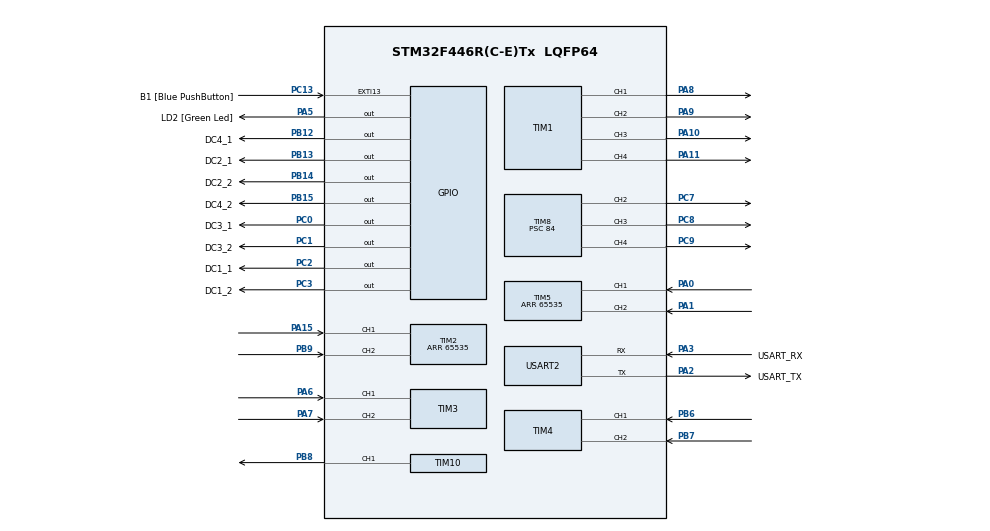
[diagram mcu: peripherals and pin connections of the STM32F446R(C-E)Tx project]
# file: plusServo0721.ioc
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Mcu.Family=STM32F4
Mcu.Name=STM32F446R(C-E)Tx
Mcu.Package=LQFP64
NVIC.PriorityGroup=NVIC_PRIORITYGROUP_0
NVIC.TIM1_BRK_TIM9_IRQn=true\:0\:0\:false\:false\:true\:true\:true\:true
NVIC.TIM1_UP_TIM10_IRQn=true\:0\:0\:false\:false\:true\:true\:true\:true
NVIC.TIM2_IRQn=true\:0\:0\:false\:false\:true\:true\:true\:true
NVIC.TIM3_IRQn=true\:0\:0\:false\:false\:true\:true\:true\:true
NVIC.TIM4_IRQn=true\:0\:0\:false\:false\:true\:true\:true\:true
NVIC.TIM5_IRQn=true\:0\:0\:false\:false\:true\:true\:true\:true
PA0-WKUP.Signal=S_TIM5_CH1
PA1.Signal=S_TIM5_CH2
PA10.Signal=S_TIM1_CH3
PA11.Signal=S_TIM1_CH4
PA13.GPIO_Label=TMS
PA13.Mode=Serial_Wire
PA13.Signal=SYS_JTMS-SWDIO
PA14.GPIO_Label=TCK
PA14.Mode=Serial_Wire
PA14.Signal=SYS_JTCK-SWCLK
PA15.Signal=S_TIM2_CH1_ETR
PA2.GPIO_Label=USART_TX
PA2.Mode=Asynchronous
PA2.Signal=USART2_TX
PA3.GPIO_Label=USART_RX
PA3.Mode=Asynchronous
PA3.Signal=USART2_RX
PA5.GPIO_Label=LD2 [Green Led]
PA5.Signal=GPIO_Output
PA6.Signal=S_TIM3_CH1
PA7.Signal=S_TIM3_CH2
PA8.Signal=S_TIM1_CH1
PA9.Signal=S_TIM1_CH2
PB12.GPIO_Label=DC4_1
PB12.Signal=GPIO_Output
PB13.GPIO_Label=DC2_1
PB13.Signal=GPIO_Output
PB14.GPIO_Label=DC2_2
PB14.Signal=GPIO_Output
PB15.GPIO_Label=DC4_2
PB15.Signal=GPIO_Output
PB3.GPIO_Label=SWO
PB3.Signal=SYS_JTDO-SWO
PB6.Signal=S_TIM4_CH1
PB7.Signal=S_TIM4_CH2
PB8.Signal=S_TIM10_CH1
PB9.Signal=S_TIM2_CH2
PC0.GPIO_Label=DC3_1
PC0.Signal=GPIO_Output
PC1.GPIO_Label=DC3_2
PC1.Signal=GPIO_Output
PC13.GPIO_Label=B1 [Blue PushButton]
PC13.GPIO_ModeDefaultEXTI=GPIO_MODE_IT_FALLING
PC13.Signal=GPXTI13
PC14-OSC32_IN.Mode=LSE-External-Oscillator
PC14-OSC32_IN.Signal=RCC_OSC32_IN
PC15-OSC32_OUT.Mode=LSE-External-Oscillator
PC15-OSC32_OUT.Signal=RCC_OSC32_OUT
PC2.GPIO_Label=DC1_1
PC2.Signal=GPIO_Output
PC3.GPIO_Label=DC1_2
PC3.Signal=GPIO_Output
PC7.Signal=S_TIM8_CH2
PC8.Signal=S_TIM8_CH3
PC9.Signal=S_TIM8_CH4
PH0-OSC_IN.Mode=HSE-External-Oscillator
PH0-OSC_IN.Signal=RCC_OSC_IN
PH1-OSC_OUT.Mode=HSE-External-Oscillator
PH1-OSC_OUT.Signal=RCC_OSC_OUT
ProjectManager.HeapSize=0x200
ProjectManager.StackSize=0x400
ProjectManager.TargetToolchain=STM32CubeIDE
RCC.48MHZClocksFreq_Value=84000000
RCC.AHBFreq_Value=84000000
RCC.APB1CLKDivider=RCC_HCLK_DIV2
RCC.APB1Freq_Value=42000000
RCC.APB1TimFreq_Value=84000000
RCC.APB2Freq_Value=84000000
RCC.APB2TimFreq_Value=84000000
RCC.CortexFreq_Value=84000000
RCC.FLatency-AdvancedSettings=FLASH_LATENCY_2
RCC.HCLKFreq_Value=84000000
RCC.HSE_VALUE=8000000
RCC.HSI_VALUE=16000000
RCC.PLLN=336
RCC.PLLP=RCC_PLLP_DIV4
RCC.SYSCLKFreq_VALUE=84000000
RCC.SYSCLKSource=RCC_SYSCLKSOURCE_PLLCLK
RCC.USBFreq_Value=168000000
RCC.VCOOutputFreq_Value=336000000
SH.S_TIM10_CH1.0=TIM10_CH1,PWM Generation1 CH1
SH.S_TIM1_CH1.0=TIM1_CH1,PWM Generation1 CH1
SH.S_TIM1_CH2.0=TIM1_CH2,PWM Generation2 CH2
SH.S_TIM1_CH3.0=TIM1_CH3,PWM Generation3 CH3
SH.S_TIM1_CH4.0=TIM1_CH4,PWM Generation4 CH4
SH.S_TIM2_CH1_ETR.0=TIM2_CH1,Encoder_Interface
SH.S_TIM2_CH2.0=TIM2_CH2,Encoder_Interface
SH.S_TIM3_CH1.0=TIM3_CH1,Encoder_Interface
SH.S_TIM3_CH2.0=TIM3_CH2,Encoder_Interface
SH.S_TIM4_CH1.0=TIM4_CH1,Encoder_Interface
SH.S_TIM4_CH2.0=TIM4_CH2,Encoder_Interface
SH.S_TIM5_CH1.0=TIM5_CH1,Encoder_Interface
SH.S_TIM5_CH2.0=TIM5_CH2,Encoder_Interface
SH.S_TIM8_CH2.0=TIM8_CH2,PWM Generation2 CH2
SH.S_TIM8_CH3.0=TIM8_CH3,PWM Generation3 CH3
SH.S_TIM8_CH4.0=TIM8_CH4,PWM Generation4 CH4
TIM1.Channel-PWM\ Generation1\ CH1=TIM_CHANNEL_1
TIM1.Channel-PWM\ Generation2\ CH2=TIM_CHANNEL_2
TIM1.Channel-PWM\ Generation3\ CH3=TIM_CHANNEL_3
TIM1.Channel-PWM\ Generation4\ CH4=TIM_CHANNEL_4
TIM10.Channel=TIM_CHANNEL_1
TIM10.OCMode_PWM=TIM_OCMODE_PWM1
TIM2.EncoderMode=TIM_ENCODERMODE_TI12
TIM2.Period=65535
TIM3.EncoderMode=TIM_ENCODERMODE_TI12
TIM3.IC1Polarity=TIM_ICPOLARITY_FALLING
TIM3.IC2Polarity=TIM_ICPOLARITY_FALLING
TIM4.EncoderMode=TIM_ENCODERMODE_TI12
TIM5.EncoderMode=TIM_ENCODERMODE_TI12
TIM5.IC1Polarity=TIM_ICPOLARITY_FALLING
TIM5.IC2Polarity=TIM_ICPOLARITY_FALLING
TIM5.Period=65535
TIM8.Channel-PWM\ Generation2\ CH2=TIM_CHANNEL_2
TIM8.Channel-PWM\ Generation3\ CH3=TIM_CHANNEL_3
TIM8.Channel-PWM\ Generation4\ CH4=TIM_CHANNEL_4
TIM8.Prescaler=84
USART2.VirtualMode=VM_ASYNC
VP_TIM10_VS_ClockSourceINT.Mode=Enable_Timer
VP_TIM1_VS_ClockSourceINT.Mode=Internal
VP_TIM1_VS_OPM.Mode=OPM_bit
board=NUCLEO-F446RE

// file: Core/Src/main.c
/* USER CODE BEGIN Header */
/**
  ******************************************************************************
  * @file           : main.c
  * @brief          : Main program body
  ******************************************************************************
  * @attention
  *
  * Copyright (c) 2022 STMicroelectronics.
  * All rights reserved.
  *
  * This software is licensed under terms that can be found in the LICENSE file
  * in the root directory of this software component.
  * If no LICENSE file comes with this software, it is provided AS-IS.
  *
  ******************************************************************************
  */
/* USER CODE END Header */
#include "main.h"

 TIM_HandleTypeDef htim1;
TIM_HandleTypeDef htim2;
TIM_HandleTypeDef htim3;
TIM_HandleTypeDef htim4;
TIM_HandleTypeDef htim5;
TIM_HandleTypeDef htim8;
TIM_HandleTypeDef htim10;

UART_HandleTypeDef huart2;

void SystemClock_Config(void);
static void MX_GPIO_Init(void);
static void MX_USART2_UART_Init(void);
static void MX_TIM2_Init(void);
static void MX_TIM3_Init(void);
static void MX_TIM4_Init(void);
static void MX_TIM5_Init(void);
static void MX_TIM1_Init(void);
static void MX_TIM10_Init(void);
static void MX_TIM8_Init(void);

/* USER CODE BEGIN 0 */

uint32_t counter2 = 0;
uint32_t counter3 = 0;
uint32_t counter4 = 0;
uint32_t counter5 = 0;

int16_t count2 = 0;
int16_t count3 = 0;
int16_t count4 = 0;
int16_t count5 = 0;

void HAL_TIM_IC_CaptureCallback(TIM_HandleTypeDef *htim)
{
	if(htim == &htim2){
		counter2 = __HAL_TIM_GET_COUNTER(htim);
		count2 = (int16_t)counter2;
	}
	else if(htim == &htim3){
			counter3 = __HAL_TIM_GET_COUNTER(htim);
			count3 = (int16_t)counter3;
		}
	else if(htim == &htim4){
			counter4 = __HAL_TIM_GET_COUNTER(htim);
			count4 = (int16_t)counter4;
		}
	else if(htim == &htim5){
			counter5 = __HAL_TIM_GET_COUNTER(htim);
			count5 = (int16_t)counter5;
		}

}

/* USER CODE END 0 */

int main(void)
{

  /* MCU Configuration--------------------------------------------------------*/

  /* Reset of all peripherals, Initializes the Flash interface and the Systick. */
  HAL_Init();

  /* Configure the system clock */
  SystemClock_Config();

  /* Initialize all configured peripherals */
  MX_GPIO_Init();
  MX_USART2_UART_Init();
  MX_TIM2_Init();
  MX_TIM3_Init();
  MX_TIM4_Init();
  MX_TIM5_Init();
  MX_TIM1_Init();
  MX_TIM10_Init();
  MX_TIM8_Init();
  /* USER CODE BEGIN 2 */
  // Encoder
  HAL_TIM_Encoder_Start_IT(&htim2, TIM_CHANNEL_ALL);
  HAL_TIM_Encoder_Start_IT(&htim3, TIM_CHANNEL_ALL);
  HAL_TIM_Encoder_Start_IT(&htim4, TIM_CHANNEL_ALL);
  HAL_TIM_Encoder_Start_IT(&htim5, TIM_CHANNEL_ALL);

  // start DC motor PWM
  HAL_TIM_PWM_Start(&htim1, TIM_CHANNEL_1);
  HAL_TIM_PWM_Start(&htim1, TIM_CHANNEL_2);
  HAL_TIM_PWM_Start(&htim1, TIM_CHANNEL_3);
  HAL_TIM_PWM_Start(&htim1, TIM_CHANNEL_4);

  // Servo PWM
  HAL_TIM_PWM_Start(&htim8, TIM_CHANNEL_2);
  HAL_TIM_PWM_Start(&htim8, TIM_CHANNEL_3);
  HAL_TIM_PWM_Start(&htim8, TIM_CHANNEL_4);
  HAL_TIM_PWM_Start(&htim10, TIM_CHANNEL_1);
  htim8.Instance->CCR2 = 75;
  htim8.Instance->CCR3 = 75;
  htim8.Instance->CCR4 = 75;
  htim10.Instance->CCR1 = 75;
  HAL_Delay(1000);
  /*
   Encoder: TIM2~TIM5
   DC motor: TIM1
   Servo: TIM8, TIM10
   */
  /* USER CODE END 2 */

  /* Infinite loop */
  /* USER CODE BEGIN WHILE */
  while (1)
  {
	  // DC motor PWM
	  /*htim1.Instance-> CCR1 = 80;
	  htim1.Instance-> CCR2 = 80;
	  htim1.Instance-> CCR3 = 80;
	  htim1.Instance-> CCR4 = 80;*/

 	  int i=0;
 	  while(i<10)
 	  {
 		  htim8.Instance->CCR2 = 32-i;
 		  htim8.Instance->CCR3 = 37+i;
 		  htim8.Instance->CCR4 = 44-i;
 		  htim10.Instance->CCR1 = 54+i;
 		  i++;
 		  HAL_Delay(1000);
 	  }
	  // four wheels go forward
	  /*for(int i=0;i<4;i++){
	  	  		  int a=1;
	  	  		  int b=0;
	  	  		  HAL_GPIO_WritePin(GPIOC, DC1_1_Pin, a);
	  	  		  HAL_GPIO_WritePin(GPIOC, DC1_2_Pin, b);
	  	  		  HAL_GPIO_WritePin(GPIOB, DC2_1_Pin, a);
	  	  		  HAL_GPIO_WritePin(GPIOB, DC2_2_Pin, b);
	  	  		  HAL_GPIO_WritePin(GPIOC, DC3_1_Pin, a);
	  	  		  HAL_GPIO_WritePin(GPIOC, DC3_2_Pin, b);
	  	  		  HAL_GPIO_WritePin(GPIOB, DC4_1_Pin, a);
	  	  		  HAL_GPIO_WritePin(GPIOB, DC4_2_Pin, b);
	  	  		  HAL_Delay(1000);
	  }
	  // four wheels go backward
	  for(int i=0;i<4;i++){
				  int a=0;
				  int b=1;
				  HAL_GPIO_WritePin(GPIOC, DC1_1_Pin, a);
				  HAL_GPIO_WritePin(GPIOC, DC1_2_Pin, b);
	  	  		  HAL_GPIO_WritePin(GPIOB, DC2_1_Pin, a);
	  	  		  HAL_GPIO_WritePin(GPIOB, DC2_2_Pin, b);
	  	  		  HAL_GPIO_WritePin(GPIOC, DC3_1_Pin, a);
	  	  		  HAL_GPIO_WritePin(GPIOC, DC3_2_Pin, b);
	  	  		  HAL_GPIO_WritePin(GPIOB, DC4_1_Pin, a);
	  	  		  HAL_GPIO_WritePin(GPIOB, DC4_2_Pin, b);
				  HAL_Delay(1000);
	  }*/

    /* USER CODE END WHILE */

    /* USER CODE BEGIN 3 */
  }
  htim1.Instance-> CCR1 = 0;
  htim1.Instance-> CCR2 = 0;
  htim1.Instance-> CCR3 = 0;
  htim1.Instance-> CCR4 = 0;
  for(int i=0;i<4;i++){
	  int a=0;
	  int b=0;
	  HAL_GPIO_WritePin(GPIOC, DC1_1_Pin, a);
	  HAL_GPIO_WritePin(GPIOC, DC1_2_Pin, b);
	  HAL_GPIO_WritePin(GPIOC, DC3_1_Pin, a);
	  HAL_GPIO_WritePin(GPIOC, DC3_2_Pin, b);
	  HAL_Delay(1000);
  }
  /* USER CODE END 3 */
}

void SystemClock_Config(void)
{
  RCC_OscInitTypeDef RCC_OscInitStruct = {0};
  RCC_ClkInitTypeDef RCC_ClkInitStruct = {0};

  /** Configure the main internal regulator output voltage
  */
  __HAL_RCC_PWR_CLK_ENABLE();
  __HAL_PWR_VOLTAGESCALING_CONFIG(PWR_REGULATOR_VOLTAGE_SCALE3);

  /** Initializes the RCC Oscillators according to the specified parameters
  * in the RCC_OscInitTypeDef structure.
  */
  RCC_OscInitStruct.OscillatorType = RCC_OSCILLATORTYPE_HSI;
  RCC_OscInitStruct.HSIState = RCC_HSI_ON;
  RCC_OscInitStruct.HSICalibrationValue = RCC_HSICALIBRATION_DEFAULT;
  RCC_OscInitStruct.PLL.PLLState = RCC_PLL_ON;
  RCC_OscInitStruct.PLL.PLLSource = RCC_PLLSOURCE_HSI;
  RCC_OscInitStruct.PLL.PLLM = 8;
  RCC_OscInitStruct.PLL.PLLN = 90;
  RCC_OscInitStruct.PLL.PLLP = RCC_PLLP_DIV2;
  RCC_OscInitStruct.PLL.PLLQ = 2;
  RCC_OscInitStruct.PLL.PLLR = 2;
  if (HAL_RCC_OscConfig(&RCC_OscInitStruct) != HAL_OK)
  {
    Error_Handler();
  }

  /** Initializes the CPU, AHB and APB buses clocks
  */
  RCC_ClkInitStruct.ClockType = RCC_CLOCKTYPE_HCLK|RCC_CLOCKTYPE_SYSCLK
                              |RCC_CLOCKTYPE_PCLK1|RCC_CLOCKTYPE_PCLK2;
  RCC_ClkInitStruct.SYSCLKSource = RCC_SYSCLKSOURCE_PLLCLK;
  RCC_ClkInitStruct.AHBCLKDivider = RCC_SYSCLK_DIV1;
  RCC_ClkInitStruct.APB1CLKDivider = RCC_HCLK_DIV4;
  RCC_ClkInitStruct.APB2CLKDivider = RCC_HCLK_DIV1;

  if (HAL_RCC_ClockConfig(&RCC_ClkInitStruct, FLASH_LATENCY_2) != HAL_OK)
  {
    Error_Handler();
  }
}

static void MX_TIM1_Init(void)
{

  TIM_ClockConfigTypeDef sClockSourceConfig = {0};
  TIM_MasterConfigTypeDef sMasterConfig = {0};
  TIM_OC_InitTypeDef sConfigOC = {0};
  TIM_BreakDeadTimeConfigTypeDef sBreakDeadTimeConfig = {0};

  htim1.Instance = TIM1;
  htim1.Init.Prescaler = 0;
  htim1.Init.CounterMode = TIM_COUNTERMODE_UP;
  htim1.Init.Period = 65535;
  htim1.Init.ClockDivision = TIM_CLOCKDIVISION_DIV1;
  htim1.Init.RepetitionCounter = 0;
  htim1.Init.AutoReloadPreload = TIM_AUTORELOAD_PRELOAD_DISABLE;
  if (HAL_TIM_Base_Init(&htim1) != HAL_OK)
  {
    Error_Handler();
  }
  sClockSourceConfig.ClockSource = TIM_CLOCKSOURCE_INTERNAL;
  if (HAL_TIM_ConfigClockSource(&htim1, &sClockSourceConfig) != HAL_OK)
  {
    Error_Handler();
  }
  if (HAL_TIM_PWM_Init(&htim1) != HAL_OK)
  {
    Error_Handler();
  }
  if (HAL_TIM_OnePulse_Init(&htim1, TIM_OPMODE_SINGLE) != HAL_OK)
  {
    Error_Handler();
  }
  sMasterConfig.MasterOutputTrigger = TIM_TRGO_RESET;
  sMasterConfig.MasterSlaveMode = TIM_MASTERSLAVEMODE_DISABLE;
  if (HAL_TIMEx_MasterConfigSynchronization(&htim1, &sMasterConfig) != HAL_OK)
  {
    Error_Handler();
  }
  sConfigOC.OCMode = TIM_OCMODE_PWM1;
  sConfigOC.Pulse = 0;
  sConfigOC.OCPolarity = TIM_OCPOLARITY_HIGH;
  sConfigOC.OCNPolarity = TIM_OCNPOLARITY_HIGH;
  sConfigOC.OCFastMode = TIM_OCFAST_DISABLE;
  sConfigOC.OCIdleState = TIM_OCIDLESTATE_RESET;
  sConfigOC.OCNIdleState = TIM_OCNIDLESTATE_RESET;
  if (HAL_TIM_PWM_ConfigChannel(&htim1, &sConfigOC, TIM_CHANNEL_1) != HAL_OK)
  {
    Error_Handler();
  }
  if (HAL_TIM_PWM_ConfigChannel(&htim1, &sConfigOC, TIM_CHANNEL_2) != HAL_OK)
  {
    Error_Handler();
  }
  if (HAL_TIM_PWM_ConfigChannel(&htim1, &sConfigOC, TIM_CHANNEL_3) != HAL_OK)
  {
    Error_Handler();
  }
  if (HAL_TIM_PWM_ConfigChannel(&htim1, &sConfigOC, TIM_CHANNEL_4) != HAL_OK)
  {
    Error_Handler();
  }
  sBreakDeadTimeConfig.OffStateRunMode = TIM_OSSR_DISABLE;
  sBreakDeadTimeConfig.OffStateIDLEMode = TIM_OSSI_DISABLE;
  sBreakDeadTimeConfig.LockLevel = TIM_LOCKLEVEL_OFF;
  sBreakDeadTimeConfig.DeadTime = 0;
  sBreakDeadTimeConfig.BreakState = TIM_BREAK_DISABLE;
  sBreakDeadTimeConfig.BreakPolarity = TIM_BREAKPOLARITY_HIGH;
  sBreakDeadTimeConfig.AutomaticOutput = TIM_AUTOMATICOUTPUT_DISABLE;
  if (HAL_TIMEx_ConfigBreakDeadTime(&htim1, &sBreakDeadTimeConfig) != HAL_OK)
  {
    Error_Handler();
  }
  HAL_TIM_MspPostInit(&htim1);

}

static void MX_TIM2_Init(void)
{

  TIM_Encoder_InitTypeDef sConfig = {0};
  TIM_MasterConfigTypeDef sMasterConfig = {0};

  htim2.Instance = TIM2;
  htim2.Init.Prescaler = 0;
  htim2.Init.CounterMode = TIM_COUNTERMODE_UP;
  htim2.Init.Period = 65535;
  htim2.Init.ClockDivision = TIM_CLOCKDIVISION_DIV1;
  htim2.Init.AutoReloadPreload = TIM_AUTORELOAD_PRELOAD_DISABLE;
  sConfig.EncoderMode = TIM_ENCODERMODE_TI12;
  sConfig.IC1Polarity = TIM_ICPOLARITY_RISING;
  sConfig.IC1Selection = TIM_ICSELECTION_DIRECTTI;
  sConfig.IC1Prescaler = TIM_ICPSC_DIV1;
  sConfig.IC1Filter = 0;
  sConfig.IC2Polarity = TIM_ICPOLARITY_RISING;
  sConfig.IC2Selection = TIM_ICSELECTION_DIRECTTI;
  sConfig.IC2Prescaler = TIM_ICPSC_DIV1;
  sConfig.IC2Filter = 0;
  if (HAL_TIM_Encoder_Init(&htim2, &sConfig) != HAL_OK)
  {
    Error_Handler();
  }
  sMasterConfig.MasterOutputTrigger = TIM_TRGO_RESET;
  sMasterConfig.MasterSlaveMode = TIM_MASTERSLAVEMODE_DISABLE;
  if (HAL_TIMEx_MasterConfigSynchronization(&htim2, &sMasterConfig) != HAL_OK)
  {
    Error_Handler();
  }

}

static void MX_TIM3_Init(void)
{

  TIM_Encoder_InitTypeDef sConfig = {0};
  TIM_MasterConfigTypeDef sMasterConfig = {0};

  htim3.Instance = TIM3;
  htim3.Init.Prescaler = 0;
  htim3.Init.CounterMode = TIM_COUNTERMODE_UP;
  htim3.Init.Period = 65535;
  htim3.Init.ClockDivision = TIM_CLOCKDIVISION_DIV1;
  htim3.Init.AutoReloadPreload = TIM_AUTORELOAD_PRELOAD_DISABLE;
  sConfig.EncoderMode = TIM_ENCODERMODE_TI12;
  sConfig.IC1Polarity = TIM_ICPOLARITY_FALLING;
  sConfig.IC1Selection = TIM_ICSELECTION_DIRECTTI;
  sConfig.IC1Prescaler = TIM_ICPSC_DIV1;
  sConfig.IC1Filter = 0;
  sConfig.IC2Polarity = TIM_ICPOLARITY_FALLING;
  sConfig.IC2Selection = TIM_ICSELECTION_DIRECTTI;
  sConfig.IC2Prescaler = TIM_ICPSC_DIV1;
  sConfig.IC2Filter = 0;
  if (HAL_TIM_Encoder_Init(&htim3, &sConfig) != HAL_OK)
  {
    Error_Handler();
  }
  sMasterConfig.MasterOutputTrigger = TIM_TRGO_RESET;
  sMasterConfig.MasterSlaveMode = TIM_MASTERSLAVEMODE_DISABLE;
  if (HAL_TIMEx_MasterConfigSynchronization(&htim3, &sMasterConfig) != HAL_OK)
  {
    Error_Handler();
  }

}

static void MX_TIM4_Init(void)
{

  TIM_Encoder_InitTypeDef sConfig = {0};
  TIM_MasterConfigTypeDef sMasterConfig = {0};

  htim4.Instance = TIM4;
  htim4.Init.Prescaler = 0;
  htim4.Init.CounterMode = TIM_COUNTERMODE_UP;
  htim4.Init.Period = 65535;
  htim4.Init.ClockDivision = TIM_CLOCKDIVISION_DIV1;
  htim4.Init.AutoReloadPreload = TIM_AUTORELOAD_PRELOAD_DISABLE;
  sConfig.EncoderMode = TIM_ENCODERMODE_TI12;
  sConfig.IC1Polarity = TIM_ICPOLARITY_RISING;
  sConfig.IC1Selection = TIM_ICSELECTION_DIRECTTI;
  sConfig.IC1Prescaler = TIM_ICPSC_DIV1;
  sConfig.IC1Filter = 0;
  sConfig.IC2Polarity = TIM_ICPOLARITY_RISING;
  sConfig.IC2Selection = TIM_ICSELECTION_DIRECTTI;
  sConfig.IC2Prescaler = TIM_ICPSC_DIV1;
  sConfig.IC2Filter = 0;
  if (HAL_TIM_Encoder_Init(&htim4, &sConfig) != HAL_OK)
  {
    Error_Handler();
  }
  sMasterConfig.MasterOutputTrigger = TIM_TRGO_RESET;
  sMasterConfig.MasterSlaveMode = TIM_MASTERSLAVEMODE_DISABLE;
  if (HAL_TIMEx_MasterConfigSynchronization(&htim4, &sMasterConfig) != HAL_OK)
  {
    Error_Handler();
  }

}

static void MX_TIM5_Init(void)
{

  TIM_Encoder_InitTypeDef sConfig = {0};
  TIM_MasterConfigTypeDef sMasterConfig = {0};

  htim5.Instance = TIM5;
  htim5.Init.Prescaler = 0;
  htim5.Init.CounterMode = TIM_COUNTERMODE_UP;
  htim5.Init.Period = 65535;
  htim5.Init.ClockDivision = TIM_CLOCKDIVISION_DIV1;
  htim5.Init.AutoReloadPreload = TIM_AUTORELOAD_PRELOAD_DISABLE;
  sConfig.EncoderMode = TIM_ENCODERMODE_TI12;
  sConfig.IC1Polarity = TIM_ICPOLARITY_FALLING;
  sConfig.IC1Selection = TIM_ICSELECTION_DIRECTTI;
  sConfig.IC1Prescaler = TIM_ICPSC_DIV1;
  sConfig.IC1Filter = 0;
  sConfig.IC2Polarity = TIM_ICPOLARITY_FALLING;
  sConfig.IC2Selection = TIM_ICSELECTION_DIRECTTI;
  sConfig.IC2Prescaler = TIM_ICPSC_DIV1;
  sConfig.IC2Filter = 0;
  if (HAL_TIM_Encoder_Init(&htim5, &sConfig) != HAL_OK)
  {
    Error_Handler();
  }
  sMasterConfig.MasterOutputTrigger = TIM_TRGO_RESET;
  sMasterConfig.MasterSlaveMode = TIM_MASTERSLAVEMODE_DISABLE;
  if (HAL_TIMEx_MasterConfigSynchronization(&htim5, &sMasterConfig) != HAL_OK)
  {
    Error_Handler();
  }

}

static void MX_TIM8_Init(void)
{

  TIM_MasterConfigTypeDef sMasterConfig = {0};
  TIM_OC_InitTypeDef sConfigOC = {0};
  TIM_BreakDeadTimeConfigTypeDef sBreakDeadTimeConfig = {0};

  htim8.Instance = TIM8;
  htim8.Init.Prescaler = 0;
  htim8.Init.CounterMode = TIM_COUNTERMODE_UP;
  htim8.Init.Period = 65535;
  htim8.Init.ClockDivision = TIM_CLOCKDIVISION_DIV1;
  htim8.Init.RepetitionCounter = 0;
  htim8.Init.AutoReloadPreload = TIM_AUTORELOAD_PRELOAD_DISABLE;
  if (HAL_TIM_PWM_Init(&htim8) != HAL_OK)
  {
    Error_Handler();
  }
  sMasterConfig.MasterOutputTrigger = TIM_TRGO_RESET;
  sMasterConfig.MasterSlaveMode = TIM_MASTERSLAVEMODE_DISABLE;
  if (HAL_TIMEx_MasterConfigSynchronization(&htim8, &sMasterConfig) != HAL_OK)
  {
    Error_Handler();
  }
  sConfigOC.OCMode = TIM_OCMODE_PWM1;
  sConfigOC.Pulse = 0;
  sConfigOC.OCPolarity = TIM_OCPOLARITY_HIGH;
  sConfigOC.OCNPolarity = TIM_OCNPOLARITY_HIGH;
  sConfigOC.OCFastMode = TIM_OCFAST_DISABLE;
  sConfigOC.OCIdleState = TIM_OCIDLESTATE_RESET;
  sConfigOC.OCNIdleState = TIM_OCNIDLESTATE_RESET;
  if (HAL_TIM_PWM_ConfigChannel(&htim8, &sConfigOC, TIM_CHANNEL_2) != HAL_OK)
  {
    Error_Handler();
  }
  if (HAL_TIM_PWM_ConfigChannel(&htim8, &sConfigOC, TIM_CHANNEL_3) != HAL_OK)
  {
    Error_Handler();
  }
  if (HAL_TIM_PWM_ConfigChannel(&htim8, &sConfigOC, TIM_CHANNEL_4) != HAL_OK)
  {
    Error_Handler();
  }
  sBreakDeadTimeConfig.OffStateRunMode = TIM_OSSR_DISABLE;
  sBreakDeadTimeConfig.OffStateIDLEMode = TIM_OSSI_DISABLE;
  sBreakDeadTimeConfig.LockLevel = TIM_LOCKLEVEL_OFF;
  sBreakDeadTimeConfig.DeadTime = 0;
  sBreakDeadTimeConfig.BreakState = TIM_BREAK_DISABLE;
  sBreakDeadTimeConfig.BreakPolarity = TIM_BREAKPOLARITY_HIGH;
  sBreakDeadTimeConfig.AutomaticOutput = TIM_AUTOMATICOUTPUT_DISABLE;
  if (HAL_TIMEx_ConfigBreakDeadTime(&htim8, &sBreakDeadTimeConfig) != HAL_OK)
  {
    Error_Handler();
  }
  HAL_TIM_MspPostInit(&htim8);

}

static void MX_TIM10_Init(void)
{

  TIM_OC_InitTypeDef sConfigOC = {0};

  htim10.Instance = TIM10;
  htim10.Init.Prescaler = 0;
  htim10.Init.CounterMode = TIM_COUNTERMODE_UP;
  htim10.Init.Period = 65535;
  htim10.Init.ClockDivision = TIM_CLOCKDIVISION_DIV1;
  htim10.Init.AutoReloadPreload = TIM_AUTORELOAD_PRELOAD_DISABLE;
  if (HAL_TIM_Base_Init(&htim10) != HAL_OK)
  {
    Error_Handler();
  }
  if (HAL_TIM_PWM_Init(&htim10) != HAL_OK)
  {
    Error_Handler();
  }
  sConfigOC.OCMode = TIM_OCMODE_PWM1;
  sConfigOC.Pulse = 0;
  sConfigOC.OCPolarity = TIM_OCPOLARITY_HIGH;
  sConfigOC.OCFastMode = TIM_OCFAST_DISABLE;
  if (HAL_TIM_PWM_ConfigChannel(&htim10, &sConfigOC, TIM_CHANNEL_1) != HAL_OK)
  {
    Error_Handler();
  }
  HAL_TIM_MspPostInit(&htim10);

}

static void MX_USART2_UART_Init(void)
{

  huart2.Instance = USART2;
  huart2.Init.BaudRate = 115200;
  huart2.Init.WordLength = UART_WORDLENGTH_8B;
  huart2.Init.StopBits = UART_STOPBITS_1;
  huart2.Init.Parity = UART_PARITY_NONE;
  huart2.Init.Mode = UART_MODE_TX_RX;
  huart2.Init.HwFlowCtl = UART_HWCONTROL_NONE;
  huart2.Init.OverSampling = UART_OVERSAMPLING_16;
  if (HAL_UART_Init(&huart2) != HAL_OK)
  {
    Error_Handler();
  }

}

static void MX_GPIO_Init(void)
{
  GPIO_InitTypeDef GPIO_InitStruct = {0};

  /* GPIO Ports Clock Enable */
  __HAL_RCC_GPIOC_CLK_ENABLE();
  __HAL_RCC_GPIOH_CLK_ENABLE();
  __HAL_RCC_GPIOA_CLK_ENABLE();
  __HAL_RCC_GPIOB_CLK_ENABLE();

  /*Configure GPIO pin Output Level */
  HAL_GPIO_WritePin(GPIOC, DC3_1_Pin|DC3_2_Pin|DC1_1_Pin|DC1_2_Pin, GPIO_PIN_RESET);

  /*Configure GPIO pin Output Level */
  HAL_GPIO_WritePin(LD2_GPIO_Port, LD2_Pin, GPIO_PIN_RESET);

  /*Configure GPIO pin Output Level */
  HAL_GPIO_WritePin(GPIOB, DC4_1_Pin|DC2_1_Pin|DC2_2_Pin|DC4_2_Pin, GPIO_PIN_RESET);

  /*Configure GPIO pin : B1_Pin */
  GPIO_InitStruct.Pin = B1_Pin;
  GPIO_InitStruct.Mode = GPIO_MODE_IT_FALLING;
  GPIO_InitStruct.Pull = GPIO_NOPULL;
  HAL_GPIO_Init(B1_GPIO_Port, &GPIO_InitStruct);

  /*Configure GPIO pins : DC3_1_Pin DC3_2_Pin DC1_1_Pin DC1_2_Pin */
  GPIO_InitStruct.Pin = DC3_1_Pin|DC3_2_Pin|DC1_1_Pin|DC1_2_Pin;
  GPIO_InitStruct.Mode = GPIO_MODE_OUTPUT_PP;
  GPIO_InitStruct.Pull = GPIO_NOPULL;
  GPIO_InitStruct.Speed = GPIO_SPEED_FREQ_LOW;
  HAL_GPIO_Init(GPIOC, &GPIO_InitStruct);

  /*Configure GPIO pin : LD2_Pin */
  GPIO_InitStruct.Pin = LD2_Pin;
  GPIO_InitStruct.Mode = GPIO_MODE_OUTPUT_PP;
  GPIO_InitStruct.Pull = GPIO_NOPULL;
  GPIO_InitStruct.Speed = GPIO_SPEED_FREQ_LOW;
  HAL_GPIO_Init(LD2_GPIO_Port, &GPIO_InitStruct);

  /*Configure GPIO pins : DC4_1_Pin DC2_1_Pin DC2_2_Pin DC4_2_Pin */
  GPIO_InitStruct.Pin = DC4_1_Pin|DC2_1_Pin|DC2_2_Pin|DC4_2_Pin;
  GPIO_InitStruct.Mode = GPIO_MODE_OUTPUT_PP;
  GPIO_InitStruct.Pull = GPIO_NOPULL;
  GPIO_InitStruct.Speed = GPIO_SPEED_FREQ_LOW;
  HAL_GPIO_Init(GPIOB, &GPIO_InitStruct);

}

void Error_Handler(void)
{
  __disable_irq();
  while (1)
  {
  }
}
